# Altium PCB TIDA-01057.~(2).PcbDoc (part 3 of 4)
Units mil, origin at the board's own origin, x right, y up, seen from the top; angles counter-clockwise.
Board outline 4448 x 3930 mil, 4 copper layers (Layer 1 - Top Layer, Layer 2 - GND, Layer 3 - PWR, Layer 4 - Bottom Layer), stack 59.034 mil thick; 536 components, 284 nets, 1540 pads, 770 vias.

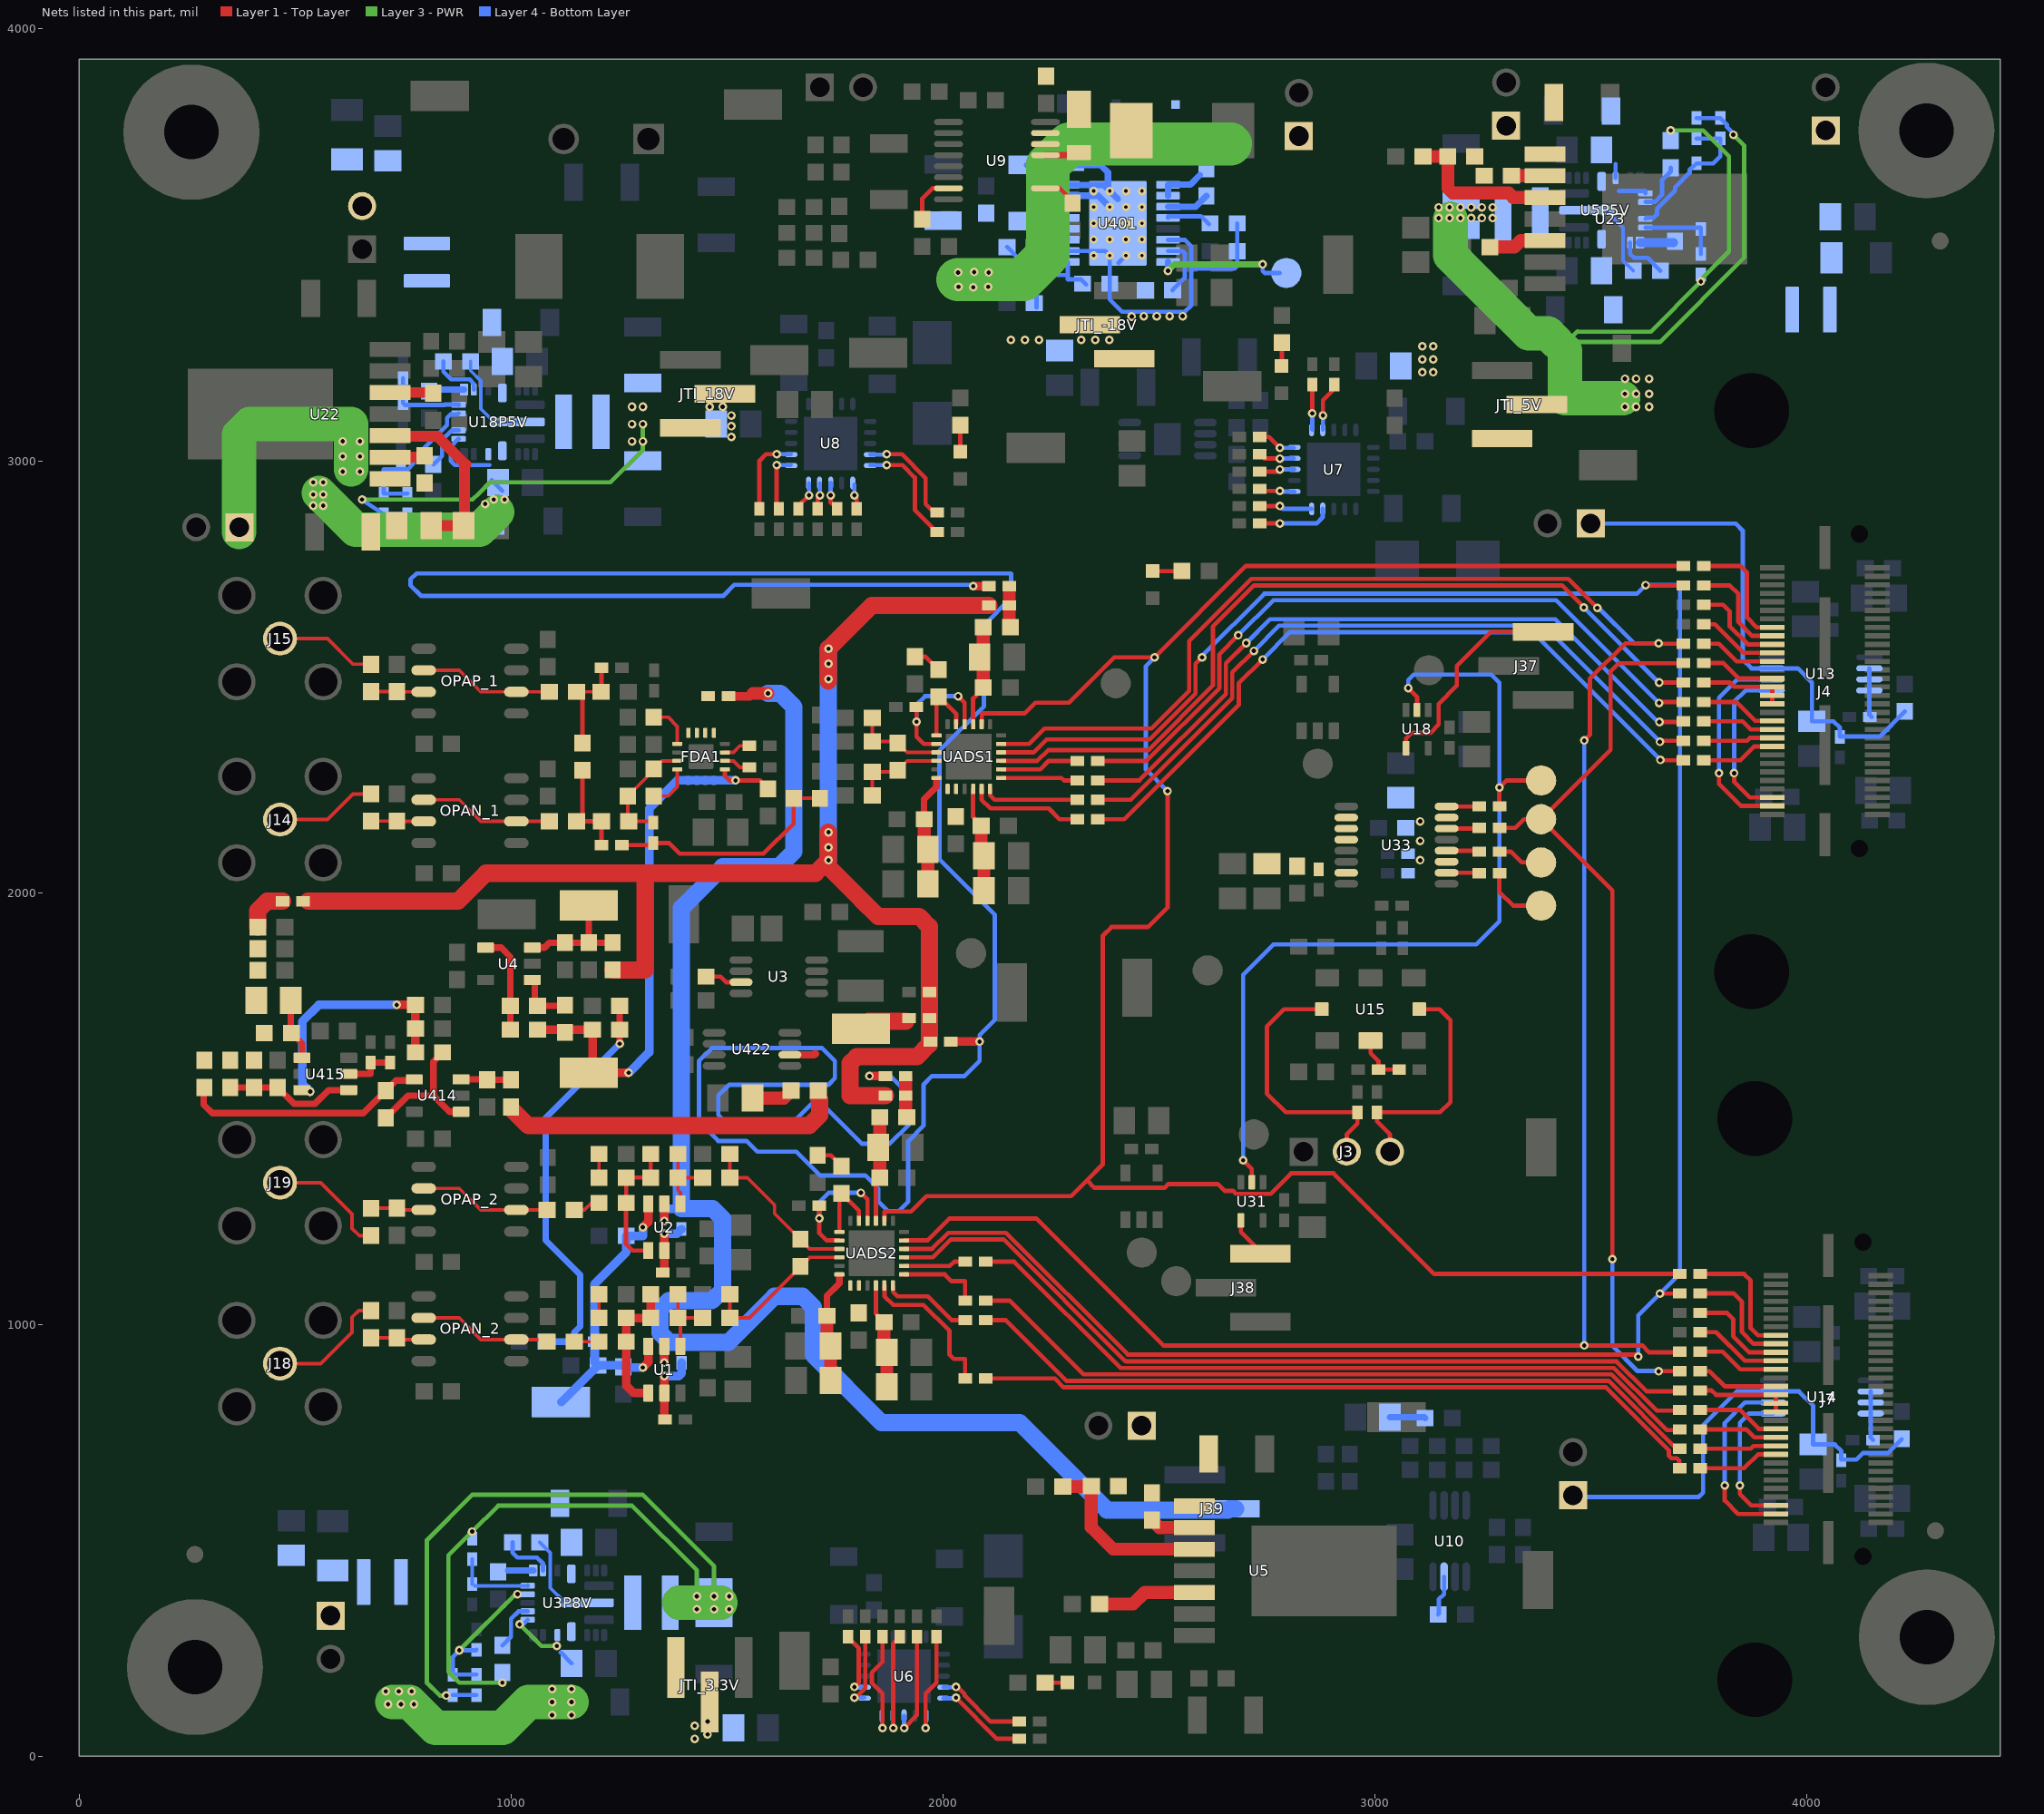
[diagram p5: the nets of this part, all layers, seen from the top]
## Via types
v1: diameter 20, hole 10, Layer 1 - Top Layer to Layer 4 - Bottom Layer, tented both sides, 382 vias
v2: diameter 20, hole 10, Layer 1 - Top Layer to Layer 4 - Bottom Layer, 258 vias
v3: diameter 20, hole 10, Layer 1 - Top Layer to Layer 4 - Bottom Layer, tented bottom, 57 vias
v4: diameter 19.68, hole 7.87, Layer 1 - Top Layer to Layer 4 - Bottom Layer, tented both sides, 48 vias
v5: diameter 20, hole 10, Layer 1 - Top Layer to Layer 4 - Bottom Layer, tented top, 19 vias
v6: diameter 19.68, hole 7.87, Layer 1 - Top Layer to Layer 4 - Bottom Layer, 6 vias

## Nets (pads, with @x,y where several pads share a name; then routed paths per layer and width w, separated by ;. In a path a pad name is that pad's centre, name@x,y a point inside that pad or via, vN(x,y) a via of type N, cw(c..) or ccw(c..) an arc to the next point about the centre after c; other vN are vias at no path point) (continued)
NetC87_2: C87.2 R100.2 RMFBP2.1 RMFBP.1 | length 557.4
  Layer 1 - Top Layer w8: C87.2@1654,2217.25 C87.2@1655,2218.25 R100.2@1715,2218.25
  Layer 1 - Top Layer w10: RMFBP.1@1256.62,2110 1324.62,2110 RMFBP2.1@1329,2114.38 1366.23,2114.38 1390.86,2089.75 1584.14,2089.75 1654,2159.6 C87.2@1654,2217.25
NetC88_2: C88.2 UADS1.13 UADS1.14
NetC89_1: C89.1 C315.1 R103.2 UADS1.10 | length 209.2
  Layer 1 - Top Layer w8: C89.1@1836.5,2224.75 R103.2@1836.5,2279.75 C315.1@1891.5,2279.75 ; C315.1@1895,2283.25 1916.65,2304.9 UADS1.10@1985.2,2304.9
NetC90_1: C90.1 C315.2 R104.2 UADS1.9 | length 209.2
  Layer 1 - Top Layer w8: C90.1@1836.5,2404.75 R104.2@1836.5,2349.75 C315.2@1891.5,2349.75 ; C315.2@1895,2346.24 1916.65,2324.59 UADS1.9@1985.2,2324.59
NetC91_2: C91.2 C287.1 L8.2 UADS1.12 | length 258.4
  Layer 1 - Top Layer w15: C91.2@1956.5,2169.75 1956.5,2216.24 1985.2,2244.94 UADS1.12@1985.2,2262.75
  Layer 1 - Top Layer w30: C91.2@1956.5,2169.75 1956.5,2108.25 C287.1@1965,2099.75 L8.2@1965,2019.75
NetC92_1: C92.1 C288.1 L9.2 UADS1.16 | length 245.6
  Layer 1 - Top Layer w10: UADS1.16@2069.84,2239.94 2069.84,2174.9 2088.5,2156.24 C92.1@2088.5,2154.75
  Layer 1 - Top Layer w30: C92.1@2088.5,2154.75 2088.5,2091.24 C288.1@2095,2084.75 L9.2@2095,2004.75
NetC93_1: C93.1 C289.1 R258.1 UADS1.3 | length 242
  Layer 1 - Top Layer w10: UADS1.3@2069.84,2389.55 2069.84,2449.59 2093.5,2473.25 C93.1@2093.5,2474.75
  Layer 1 - Top Layer w30: C93.1@2093.5,2474.75 2093.5,2536.24 C289.1@2085,2544.75 2093.5,2553.25 R258.1@2093.5,2614.75
NetC110_1: C110.1 R113.2 | length 55
  Layer 1 - Top Layer w8: C110.1@1203.5,1014.75 R113.2@1203.5,1069.75
NetC110_2: C110.2 C111.2 R114.1 RDP4.1 U1.4 | length 326.9
  Layer 1 - Top Layer w20: U1.4@1317.6,840.61 1284.13,840.61 1266.5,858.25 C110.2@1266.5,1014.75 C111.2@1323.5,1014.75 R114.1@1323.5,1069.75
NetC111_1: C111.1 R114.2 R115.1 U1.1 | length 180.3
  Layer 1 - Top Layer w8: R114.2@1386.5,1069.75 C111.1@1386.5,1014.75 ; U1.1@1392.4,948.88 1392.4,1008.84 C111.1@1386.5,1014.75 ; R115.1@1443.5,1014.75 C111.1@1386.5,1014.75
NetC113_1: C113.1 C114.2 R116.1 RDN4.1 U2.4 | length 324
  Layer 1 - Top Layer w10: U2.4@1317.6,1170.61 1281.06,1170.61 1266.18,1185.49 1266.18,1280.68 RDN4.1@1266.5,1281 C113.1@1266.5,1339.75 C114.2@1323.5,1339.75 R116.1@1323.5,1394.75
NetC113_2: C113.2 R112.2 | length 55
  Layer 1 - Top Layer w8: C113.2@1203.5,1339.75 R112.2@1203.5,1394.75
NetC114_1: C114.1 R116.2 R117.1 U2.1 | length 175.3
  Layer 1 - Top Layer w8: R116.2@1386.5,1394.75 C114.1@1386.5,1339.75 ; U2.1@1392.4,1278.88 1392.4,1304.75 1386.5,1310.65 C114.1@1386.5,1339.75 ; R117.1@1443.5,1339.75 C114.1@1386.5,1339.75
NetC117_1: C117.1 C335.2 R117.2 UADS2.9 | length 386.5
  Layer 1 - Top Layer w8: C117.1@1506.5,1394.75 R117.2@1506.5,1339.75 1547,1339.75 1610,1276.75 1610,1256.75 C335.2@1668.5,1198.24 ; C335.2@1670,1196.24 1691.65,1174.59 UADS2.9@1760.2,1174.59
NetC118_1: C118.1 C335.1 R115.2 UADS2.10 | length 364.4
  Layer 1 - Top Layer w8: C118.1@1506.5,1069.75 R115.2@1506.5,1014.75 1552,1014.75 C335.1@1668.5,1131.25 ; C335.1@1670,1133.25 1691.65,1154.9 UADS2.10@1760.2,1154.9
NetC119_1: C119.1 UADS2.13 UADS2.14
NetC120_2: C120.2 C306.1 L6.2 UADS2.12 | length 258.4
  Layer 1 - Top Layer w15: C120.2@1731.5,1019.75 1731.5,1066.24 1760.2,1094.94 UADS2.12@1760.2,1112.75
  Layer 1 - Top Layer w30: C120.2@1731.5,1019.75 1731.5,958.25 C306.1@1740,949.75 L6.2@1740,869.75
NetC121_1: C121.1 C307.1 L7.2 UADS2.16 | length 245.6
  Layer 1 - Top Layer w10: UADS2.16@1844.84,1089.94 1844.84,1024.9 1863.5,1006.24 C121.1@1863.5,1004.75
  Layer 1 - Top Layer w30: C121.1@1863.5,1004.75 1863.5,941.24 C307.1@1870,934.75 L7.2@1870,854.75
NetC122_1: C122.1 C308.1 R261.1 UADS2.3 | length 247.2
  Layer 1 - Top Layer w10: UADS2.3@1844.84,1239.55 C122.1@1844.84,1339.75
  Layer 1 - Top Layer w30: C122.1@1853.5,1339.75 1853.5,1401.24 1845,1409.75 1853.5,1418.25 R261.1@1853.5,1479.75
NetC316_1: C316.1 FDA1.4 | length 104.3
  Layer 1 - Top Layer w8: C316.1@1330,2223.25 1363.5,2223.25 1384.88,2244.63 FDA1.4@1384.88,2285.22
NetC316_2: C316.2 FDA1.3 R99.2 RDP2.1 RMFBP2.2 | length 267.6
  Layer 1 - Top Layer w8: RMFBP2.2@1329,2161.62 1325.62,2165 RDP2.1@1272.5,2165 1270,2167.5 R99.2@1270,2223.25 1330,2283.25 C316.2@1330,2286.24 1348.66,2304.9 FDA1.3@1384.88,2304.9
NetC317_1: C317.1 FDA1.1 | length 104.3
  Layer 1 - Top Layer w8: C317.1@1330,2406.24 1363.5,2406.24 1384.88,2384.86 FDA1.1@1384.88,2344.27
NetC319_1: C319.1 R215.1 U4.1 | length 129.5
  Layer 1 - Top Layer w15: U4.1@1049.13,1797.6 1055,1791.74 1055,1743.87 C319.1@1061.5,1737.38 1123.5,1737.38 R215.1@1125,1738.87
NetC319_2: C319.2 R216.1 U4.4 | length 235.2
  Layer 1 - Top Layer w15: U4.4@940.87,1872.41 977.28,1872.41 998.5,1851.19 C319.2@998.5,1737.38 R216.1@998.5,1682.38
NetC321_1: C321.1 R217.2 R218.1 TP28.1 U4.3 | length 276.7
  Layer 1 - Top Layer w15: U4.3@1049.13,1872.41 1077.4,1872.41 1088.87,1883.87 C321.1@1125,1883.87 R217.2@1180,1883.87 ; TP28.1@1180,1970 R217.2@1180,1883.87 ; R218.1@1235,1883.87 R217.2@1180,1883.87
NetC322_2: C322.2 R268.2 | length 67.4
  Layer 1 - Top Layer w10: R268.2@1935,2546.24 1960,2546.24 C322.2@1990,2516.24
NetC323_2: C323.2 R269.2 | length 65.4
  Layer 1 - Top Layer w10: R269.2@1710,1391.24 1740,1391.24 C323.2@1765,1366.24
NetC355_1: C355.1 C356.1 JSI_3.3V.1 L20.1
NetC357_1: C357.1 C358.1 C359.1 C360.1 L20.2 U3P8V.4 U3P8V.14 U3P8V.15 U3P8V.18 | length 619.3
  Layer 3 - PWR w10: v2(1020,305) 1070,255 v3(1106,255)
  Layer 3 - PWR w80: 725,125 760,125 765.29,125 825.29,65 980,65 1040,125 v2(1095,125) v2(1140,125)
  Layer 4 - Bottom Layer w10: v2@1029.61,306.77 U3P8V.18@1038.46,315.63 ; C360.1@1115,240 C360.1@1140,215
  other v2: 1095,95 715,120 745,120 775,120 740,150 1095,155
  other v3: 1140,95 710,150 770,150 1140,155
NetC361_1: C361.1 U3P8V.2 | length 120.7
  Layer 4 - Bottom Layer w10: C361.1@1003.5,495 1003.5,471.5 1015,460 1060,460 1073.9,446.1 U3P8V.2@1073.9,429.8
NetC361_2: C361.2 L21.1 U3P8V.9 | length 164.7
  Layer 4 - Bottom Layer w8: C361.2@1066.5,495 1090.63,470.87 1090.63,389.37 1108,372 1108.73,372 1114,366.73 1114,366 U3P8V.9@1125,355
NetC362_1: C362.1 RB3.1 U3P8V.22 | length 181.2
  Layer 4 - Bottom Layer w8: C362.1@910,398.62 RB3.1@910,456.38 ; C362.1@915.63,394.37 U3P8V.22@1038.46,394.37
  Layer 4 - Bottom Layer w10: U3P8V.22@1038.46,394.37 U3P8V.22@1038.46,395
NetC363_1: C363.1 R290.2 R291.2 U3P8V.21 | length 347
  Layer 1 - Top Layer w10: v2@1010,375 v2(1015,375)
  Layer 3 - PWR w10: v2(880,245) v2@1010,375
  Layer 4 - Bottom Layer w10: C363.1@920,188.62 R291.2@865,188.62 865,230 v2(880,245) 918.62,245 R290.2@920,246.38
NetC363_2: C363.2 C364.1 C366.1 JTI_3.3V.1 L21.2 R291.1 RB3.2 RES3V.1 | length 2534.4
  Layer 3 - PWR w10: v3(850,140) 835,140 805,170 805,500 910,605 1305,605 1470,440 v2(1470,370) ; v3(980,170) 880,170 855,195 855,465 v3(910,520) 970,580 1280,580 1430,430 v2(1430,370)
  Layer 3 - PWR w80: 1389.96,355 1485,355
  Layer 4 - Bottom Layer w10: R291.1@865,141.38 C363.2@920,141.38
  other v2: 1430,340 1470,340 1505,340 1505,370
NetC367_1: C367.1 C368.1 JSI_5V.1 L22.1
NetC369_1: C369.1 C370.1 C371.1 C372.1 L22.2 U5P5V.4 U5P5V.14 U5P5V.15 U5P5V.18 | length 100
  Layer 4 - Bottom Layer w10: U5P5V.15@3557.64,3654.8 3557.64,3687.64 ; 3565,3625 3626.54,3625 U5P5V.18@3626.54,3619.37
NetC373_1: C373.1 U5P5V.2 | length 114.7
  Layer 4 - Bottom Layer w10: U5P5V.2@3589.75,3503.85 U5P5V.2@3591.1,3505.2 3591.1,3478.9 3600,3470 3631.5,3470 C373.1@3661.5,3440
NetC373_2: C373.2 L23.1 U5P5V.9 | length 166.3
  Layer 4 - Bottom Layer w8: U5P5V.9@3535,3580 3575,3540 3575,3463.5 C373.2@3598.5,3440
NetC374_1: C374.1 R294.2 R295.2 U5P5V.21 | length 345.6
  Layer 4 - Bottom Layer w10: U5P5V.21@3626.54,3560.31 3629.33,3563.11 3645.8,3563.11 3653.27,3570.58 3653.27,3583.27 3695.13,3625.13 3695.13,3633.21 3729.05,3667.13 3729.05,3674.05 3730,3675 R294.2@3745,3688.62 3783.62,3688.62 3800,3705 R295.2@3800,3746.38 C374.1@3745,3746.38
NetC374_2: C374.2 C376.1 C378.1 JTI_5V.1 L23.2 R295.1 RB5.2 RES5V.1 | length 2441.5
  Layer 3 - PWR w10: 3420,3275 3445.2,3275 ; 3440,3255 3440,3269.8 3445.2,3275 ; v3(3685,3765) 3760,3765 3820,3705 3820,3485 3755,3420 v3(3755,3415) 3639,3299 3469.94,3299 3469.57,3299.37 3445.2,3275 ; v3(3830,3755) 3855,3730 3855,3470 3660,3275 3445.2,3275
  Layer 3 - PWR w80: v2@3175,3560 3175,3476 3356,3295 3400,3295 3420,3275 ; 3440,3255 3440,3145 3575,3145
  Layer 4 - Bottom Layer w10: C374.2@3745,3793.62 R295.1@3800,3793.62 3815,3778.62 3815,3773.08 3830,3758.08 v3(3830,3755)
  other v2: 3579,3125 3605,3125 3635,3125 3579,3155 3605,3155 3635,3155 3579,3190 3605,3190 3635,3190 3148,3562 3173,3562 3198,3562 3223,3562 3248,3562 3273,3562 3148,3587 3173,3587 3198,3587 3223,3587 3248,3587 3273,3587
NetC375_1: C375.1 RB5.1 U5P5V.22 | length 187.7
  Layer 4 - Bottom Layer w10: RB5.1@3755,3478.62 C375.1@3755,3536.38 ; C375.1@3755,3540 U5P5V.22@3627.17,3540 ; U5P5V.22@3627.17,3540 3626.54,3540 U5P5V.22@3626.54,3540.63 U5P5V.22@3627.17,3540
NetC379_1: C379.1 C380.1 JSI_18V.2 L24.1
NetC381_1: C381.1 C382.1 C383.1 C384.1 L24.2 U18P5V.4 U18P5V.14 U18P5V.15 U18P5V.18 | length 653
  Layer 3 - PWR w80: 555,2925 640,2840 927,2840 968,2881
  Layer 4 - Bottom Layer w10: U18P5V.18@878.46,3050.63 860,3032.17 860,3000 870,2990 950,2990 ; C384.1@955,2955 C384.1@980,2930
  other v2: 542,2896 565,2896 940,2900 985,2910 542,2922 565,2922 542,2950 565,2950
  other v3: 960,2910
NetC385_1: C385.1 U18P5V.2 | length 120.7
  Layer 4 - Bottom Layer w10: C385.1@843.5,3230 843.5,3206.5 861.42,3188.58 903.8,3188.58 913.9,3178.49 U18P5V.2@913.9,3164.8 U18P5V.2@915,3165.91
NetC385_2: C385.2 L25.1 U18P5V.9 | length 216.5
  Layer 4 - Bottom Layer w8: C385.2@906.5,3230 906.5,3208.5 929.79,3185.21 929.79,3120.15 959.94,3090 U18P5V.9@1014.29,3090
NetC387_1: C387.1 R297.2 R298.2 U18P5V.21 | length 354.8
  Layer 4 - Bottom Layer w10: C387.1@760,2923.62 R298.2@705,2923.62 705,2980 760,2980 775,2995 775,3006.22 851.73,3082.95 851.73,3099.42 859.2,3106.89 875.67,3106.89 U18P5V.21@878.46,3109.69
NetC387_2: C387.2 C389.1 C391.1 JTI_18V.1 L25.2 R298.1 | length 862.9
  Layer 3 - PWR w10: v2(655,2910) 911,2910 926,2925 951,2950 1230,2950 1305,3025 1305,3075
  Layer 4 - Bottom Layer w10: v2(655,2910) R298.1@705,2876.38 C387.2@760,2876.38
  other v2: 1280,3045 1305,3045 1280,3125 1305,3125
  other v3: 1280,3085 1305,3085
NetC388_1: C388.1 RB18.1 U18P5V.22 | length 188.9
  Layer 4 - Bottom Layer w10: RB18.1@750,3191.38 C388.1@750,3133.62 754.25,3129.37 846.09,3129.37 846.72,3130 878.46,3130 U18P5V.22@878.46,3129.37
NetC401_1: C401.1 C402.1 C408.1 JPRI_-18V.1 U401.12 U401.13 U401.14 | length 882.9
  Layer 3 - PWR w100: 2035,3420 2186,3420 2243,3477 2243,3685 2292,3734 2666,3734
  other v2: 2070,3402 2036,3403 2105,3403 2035,3436 2106,3436 2072,3437
NetC403_1: C403.1 U401.4 | length 106
  Layer 4 - Bottom Layer w10: U401.4@2521.14,3562.8 2521.14,3566.18 2597.32,3566.18 C403.1@2616,3547.5
NetC403_2: C403.2 C405.2 C406.2 C407.2 C408.2 JTI_-18V.3 R401.1 R404.1 U401.6 U401.10 U401.15 U401.16 U401.17@2405,3550 | length 1487.3
  Layer 4 - Bottom Layer w10: C407.2@2148.5,3495 2173.5,3470 2183.97,3470 2187.67,3466.3 2235.32,3466.3 2255.05,3486.02 U401.10@2288.86,3486.02 2338.07,3486.02 ; U401.16@2288.86,3639.57 U401.16@2289.61,3638.82 ; v4(2348.9,3475.2) 2338.07,3486.02 ; U401.17@2406.5,3457.99 v4(2423.7,3475.2) ; v4(2461.1,3512.6) U401.17@2462.09,3511.61 ; U401.6@2521.14,3511.61 2560,3511.61 2575,3496.61 2575,3445 ; C403.2@2681.5,3550 C405.2@2681.5,3485 2681.5,3451.5 2675,3445 2575,3445 ; 2338.07,3486.02 2375.47,3486.02 v4(2386.3,3475.2) 2386.3,3373.7 2415,3345 2560,3345 2575,3360 2575,3445
  Layer 4 - Bottom Layer w15: C408.2@2195,3684.96 2365,3685 2381.93,3668.07 U401.17@2381.93,3629.17 ; U401.15@2288.86,3613.98 2359.72,3613.98 v6(2386.3,3587.4) ; U401.16@2289.61,3638.82 2372.29,3638.82 U401.17@2381.93,3629.17 ; U401.17@2405,3606.1 v4(2386.3,3624.8) U401.17@2381.93,3629.17
  other v2: 2437,3334 2465,3335 2495,3335 2525,3335 2555,3335
  other v4: 2461.1,3475.2 2348.9,3512.6 2348.9,3550 2461.1,3550 2348.9,3587.4 2461.1,3587.4 2348.9,3624.8 2423.7,3624.8 2461.1,3624.8
  other v6: 2386.3,3512.6 2423.7,3512.6 2386.3,3550 2423.7,3550 2423.7,3587.4
NetC404_1: C404.1 U401.3 | length 99.3
  Layer 4 - Bottom Layer w15: U401.3@2521.14,3588.39 2584.88,3588.39 C404.1@2610,3613.5
NetC404_2: C404.2 L401.1 U401.1 U401.2 | length 108.5
  Layer 4 - Bottom Layer w15: U401.2@2521.14,3613.98 U401.1@2521.14,3639.57 2573.07,3639.57 C404.2@2595,3661.5
NetC407_1: C407.1 U401.11 | length 87.9
  Layer 4 - Bottom Layer w11: C407.1@2211.5,3495 2230.7,3514.2 2288.86,3514.2 U401.11@2288.86,3511.61
NetC409_2: C409.2 R401.2 R402.1 U401.9 | length 230.6
  Layer 4 - Bottom Layer w10: R402.1@2211.5,3430 2288.86,3430 ; C409.2@2216.5,3355 R402.1@2216.5,3420 ; U401.9@2288.86,3460.43 2288.86,3430 ; R401.2@2331.69,3408.05 2319.75,3420 2288.86,3420 2288.86,3430
NetC452_1: C452.1 C457.1 C458.1 C459.1 C461.1 R457.1 R489.2 R492.2 R494.2 | length 105.3
  Layer 1 - Top Layer w40: C457.1@413.5,1919.75 413.5,1958.25 435,1979.75 R457.1@471.38,1979.75
NetC452_2: C452.2 R489.1 U415.1 | length 143.7
  Layer 1 - Top Layer w15: C452.2@489.55,1763.74 C452.2@489.83,1764.02 ; C452.2@490,1749.75 490,1676.24 R489.1@491.5,1674.75 515.87,1650.38 U415.1@515.87,1617.15
NetC453_1: C453.1 R485.2 U414.3 | length 115
  Layer 1 - Top Layer w15: U414.3@884.13,1567.15 C453.1@944.09,1567.15 ; C453.1@945,1566.24 R485.2@1000,1566.24
NetC454_1: C454.1 R486.2 R488.2 U415.3 | length 557.5
  Layer 1 - Top Layer w20: v5(735,1739.75) C454.1@778.5,1739.75 R488.2@778.5,1684.75 R486.2@778.5,1629.75
  Layer 4 - Bottom Layer w20: v2(534.83,1539.02) 516.8,1557.04 516.8,1701.55 555,1739.75 v5(735,1739.75)
NetC460_1: C460.1 R486.1 U414.1 | length 319.8
  Layer 1 - Top Layer w15: C460.1@710,1478.25 761.5,1529.75 820.2,1529.75 ; R486.1@841.5,1629.75 820.2,1608.45 820.2,1529.75 ; U414.1@884.13,1492.34 857.6,1492.34 820.2,1529.75
NetC460_2: C460.2 R494.1 U414.4 | length 571.6
  Layer 1 - Top Layer w15: R494.1@289.7,1548.5 288.2,1550 288.2,1508.8 308,1489 657.76,1489 C460.2@710,1541.24 733.5,1564.75 773.46,1564.75 U414.4@775.87,1567.15
NetC461_2: C461.2 R491.2 R492.1 U415.4 | length 310.8
  Layer 1 - Top Layer w15: R492.1@344.7,1542.95 R492.1@350.26,1548.5 ; R492.1@349.7,1548.5 R492.1@350.26,1548.5 ; U415.4@624.13,1542.34 577.6,1542.34 546.25,1511 496.95,1511 R491.2@459.7,1548.25 404.95,1548.25 C461.2@404.7,1548.5 R492.1@350.26,1548.5
NetCin1_1: Cin1.1 JZI_18V.1 Rent.2 Ron.2 U22.1 | length 600.4
  Layer 3 - PWR w80: JZI_18V.1@370,2835 370,3060 395,3085 630,3085 630,2980
  other v2: 610,2975 650,2975 610,3010 650,3010 610,3045 650,3045
NetCin2_1: Cin2.1 JZI_5V.1 Rent2.2 Ron2.2 U23.1
NetCin3_1: Cin3.1 JZI_3.3V.1 Rent3.2 Ron3.2 U5.1
NetCMFB_1: CMFB.1 RDP1.2 RDP2.2 RMFBP.2 | length 237.3
  Layer 1 - Top Layer w10: CMFB.1@1165,2283.25 1165,2178.25 RDP1.2@1151.5,2164.75 1209.25,2164.75 RDP2.2@1209.5,2165 1209.5,2110.13 RMFBP.2@1209.38,2110
NetCMFB_2: CMFB.2 RDN1.2 RDN2.2 RMFBN.1 | length 237.3
  Layer 1 - Top Layer w8: RDN1.2@1151.5,2464.75 RDN2.2@1208.5,2464.75 RDN2.2@1209.38,2465.62
  Layer 1 - Top Layer w10: RDN1.2@1151.5,2464.75 1165,2451.24 CMFB.2@1165,2346.24 ; RDN2.2@1209.38,2465.62 RMFBN.1@1209.38,2520.55
NetCR481_1: CR481.1 RR413.1 | length 96.5
  Layer 1 - Top Layer w30: CR481.1@1559,1524 1631.5,1524 RR413.1@1648.5,1541
NetCss2_1: Css2.1 U23.5 | length 134.1
  Layer 1 - Top Layer w30: Css2.1@3266.5,3495 3323,3495 3338,3510 U23.5@3394.37,3510
NetCss3_1: Css3.1 U5.5 | length 231.1
  Layer 1 - Top Layer w30: Css3.1@2362.5,352 2440,352 2467,379 U5.5@2582.37,379
NetCss_2: Css.2 U22.5 | length 98.9
  Layer 1 - Top Layer w25: U22.5@719.63,3158 Css.2@818.5,3158
NetCVCC3V_1: CVCC3V.1 U3P8V.1 | length 57.6
  Layer 4 - Bottom Layer w15: 993.62,429.8 U3P8V.1@1051.26,429.8
NetCVCC5V_1: CVCC5V.1 U5P5V.1 | length 82.6
  Layer 4 - Bottom Layer w10: CVCC5V.1@3691.69,3505.2 CVCC5V.1@3695,3508.5
  Layer 4 - Bottom Layer w20: U5P5V.1@3613.74,3505.2 CVCC5V.1@3691.69,3505.2
NetCVCC18V_1: CVCC18V.1 U18P5V.1 | length 82.6
  Layer 4 - Bottom Layer w15: CVCC18V.1@810,3161.5 813.31,3164.8 U18P5V.1@891.26,3164.8
NetD2_2: D2.2 U9.13 | length 80.3
  Layer 1 - Top Layer w10: D2.2@2308.99,3707.8 D2.2@2315,3713.8
  Layer 1 - Top Layer w14: U9.13@2237.2,3707.8 D2.2@2308.99,3707.8
NetD14_2: D14.2 R46.1 | length 52
  Layer 1 - Top Layer w10: R46.1@2236.5,170 D14.2@2288.5,170
NetD18_2: D18.2 R47.1 | length 67.7
  Layer 1 - Top Layer w10: D18.2@2486,2744.5 2553,2744.5 R47.1@2553.5,2745
NetD21_2: D21.2 R246.1 | length 54.5
  Layer 1 - Top Layer w10: D21.2@2783.32,3219.73 2785,3221.42 R246.1@2785,3273.5
NetD22_2: D22.2 R247.1 | length 61
  Layer 1 - Top Layer w10: D22.2@2040,3021.5 R247.1@2040,3082.52
NetFDA1_10: FDA1.10 R211.1 | length 62.5
  Layer 1 - Top Layer w8: FDA1.10@1495.12,2304.9 1514.84,2304.9 1530,2289.75 R211.1@1551.38,2289.75
NetFDA1_11: FDA1.11 R212.1 | length 62.5
  Layer 1 - Top Layer w8: FDA1.11@1495.12,2324.59 1514.84,2324.59 1530,2339.75 R212.1@1551.38,2339.75
NetFDA1_13: FDA1.13 FDA1.14 FDA1.15 FDA1.16 R248.1
NetJ4_16: J4.16 R65.2 | length 278.6
  Layer 1 - Top Layer w10: R65.2@3762.01,2756.39 3846.52,2756.39 3861.52,2741.39 3861.52,2636.88 3884.21,2614.19 J4.16@3920.51,2614.19
NetJ4_18: J4.18 R66.2 | length 245.4
  Layer 1 - Top Layer w10: R66.2@3761.36,2711.39 3821.52,2711.39 3841.52,2691.39 3841.52,2626.88 3873.91,2594.49 J4.18@3920.51,2594.49
NetJ4_20: J4.20 R67.2 | length 217.3
  Layer 1 - Top Layer w10: R67.2@3761.36,2666.39 3806.52,2666.39 3821.52,2651.39 3821.52,2616.88 3863.61,2574.79 J4.20@3920.51,2574.79
NetJ4_22: J4.22 R68.2 | length 186.6
  Layer 1 - Top Layer w10: R68.2@3761.36,2621.39 3787.01,2621.39 3853.31,2555.09 J4.22@3920.51,2555.09
NetJ4_24: J4.24 R69.2 | length 176.1
  Layer 1 - Top Layer w10: R69.2@3761.36,2576.39 3796.52,2576.39 3837.52,2535.39 J4.24@3920.51,2535.39
NetJ4_28: J4.28 R70.2 | length 173.8
  Layer 1 - Top Layer w10: R70.2@3761.36,2531.39 3807.01,2531.39 3842.41,2495.99 J4.28@3920.51,2495.99
NetJ4_30: J4.30 J4.32 J4.34 R71.2 | length 202.2
  Layer 1 - Top Layer w10: R71.2@3761.36,2486.39 3822.01,2486.39 3832.11,2476.29 J4.30@3920.02,2476.29 ; J4.34@3920.51,2436.89 J4.32@3920.51,2456.59 J4.30@3920.51,2476.29
NetJ4_38: J4.38 R72.2 | length 177.3
  Layer 1 - Top Layer w10: R72.2@3761.36,2441.39 3836.52,2441.39 3880.42,2397.49 J4.38@3920.51,2397.49
NetJ4_40: J4.40 R73.2 | length 166.8
  Layer 1 - Top Layer w10: R73.2@3761.36,2396.39 3851.52,2396.39 3870.12,2377.79 J4.40@3920.51,2377.79
NetJ4_42: J4.42 R74.2 | length 161.9
  Layer 1 - Top Layer w10: R74.2@3761.36,2351.39 3861.52,2351.39 3868.22,2358.09 J4.42@3920.51,2358.09
NetJ4_44: J4.44 R75.2 | length 172.4
  Layer 1 - Top Layer w10: R75.2@3761.36,2306.39 3846.52,2306.39 3878.52,2338.39 J4.44@3920.51,2338.39
NetJ7_16: J7.16 R76.2 | length 303.2
  Layer 1 - Top Layer w10: R76.2@3748.65,1116.69 3855.03,1116.69 3870.03,1101.69 3870.03,991.69 3887.23,974.49 J7.16@3928.52,974.49
NetJ7_18: J7.18 R77.2 | length 269.3
  Layer 1 - Top Layer w10: R77.2@3748.65,1071.69 3830.03,1071.69 3850.03,1051.69 3850.03,981.69 3876.93,954.79 J7.18@3928.52,954.79
NetJ7_20: J7.20 R78.2 | length 241.2
  Layer 1 - Top Layer w10: R78.2@3748.65,1026.69 3815.03,1026.69 3830.03,1011.69 3830.03,971.69 3866.63,935.09 J7.20@3928.52,935.09
NetJ7_22: J7.22 R79.2 | length 207.3
  Layer 1 - Top Layer w10: R79.2@3748.65,981.69 3790.03,981.69 3856.33,915.39 J7.22@3928.52,915.39
NetJ7_24: J7.24 R80.2 | length 196.9
  Layer 1 - Top Layer w10: R80.2@3748.65,936.69 3805.03,936.69 3846.03,895.69 J7.24@3928.52,895.69
NetJ7_28: J7.28 R81.2 | length 194.5
  Layer 1 - Top Layer w10: R81.2@3748.65,891.69 3775.03,891.69 3810.43,856.29 J7.28@3928.52,856.29
NetJ7_30: J7.30 J7.32 J7.34 R82.2 | length 223.5
  Layer 1 - Top Layer w10: R82.2@3748.65,846.69 3780.03,846.69 3790.13,836.59 J7.30@3928.52,836.59 J7.32@3928.52,816.89 J7.34@3928.52,797.19
NetJ7_38: J7.38 R83.2 | length 198.1
  Layer 1 - Top Layer w10: R83.2@3748.65,801.69 3845.03,801.69 3888.93,757.79 J7.38@3928.52,757.79
NetJ7_40: J7.40 R84.2 | length 187.6
  Layer 1 - Top Layer w10: R84.2@3748.65,756.69 3860.03,756.69 3878.63,738.09 J7.40@3928.52,738.09
NetJ7_42: J7.42 R85.2 | length 182.6
  Layer 1 - Top Layer w10: R85.2@3748.65,711.69 3870.03,711.69 3876.73,718.39 J7.42@3928.52,718.39
NetJ7_44: J7.44 R86.2 | length 193.1
  Layer 1 - Top Layer w10: R86.2@3748.65,666.69 3855.03,666.69 3887.03,698.69 J7.44@3928.52,698.69
NetJ37_1: J37.1 U18.4 | length 500.2
  Layer 1 - Top Layer w10: U18.4@3070.13,2332.17 U18.4@3072.22,2334.25 3072.22,2356.96 3085,2369.75 3128.38,2369.75 3147.81,2389.17 3147.81,2436.99 3190,2479.18 3190,2524.75 3268.74,2603.49 J37.1@3389.96,2603.49
NetJ38_1: J38.1 U31.4 | length 120.5
  Layer 1 - Top Layer w10: U31.4@2689.62,1240.45 2689.62,1214.26 2735.39,1168.49 J38.1@2764.96,1168.49
NetJTI_3.3V_2: JTI_3.3V.2 L19.1
  other v2: 1425,40 1455,50 1425,70 1455,80
NetJTI_5V_2: JTI_5V.2 L18.1
  other v2: 3110,3205 3135,3205 3110,3235 3135,3235 3110,3265 3135,3265
NetJTI_18V_2: JTI_18V.2 L16.2
  other v2: 1510,3055 1510,3080 1510,3105 1460,3125 1490,3125
NetJTI_-18V_2: JTI_-18V.2 L17.2
  other v2: 2157.5,3280 2190,3280 2222.5,3280 2320,3280 2352.5,3280 2385,3280
NetL5_2: L5.2 R22.2 | length 82.4
  Layer 4 - Bottom Layer w15: L5.2@3035,785 3114.52,785 R22.2@3116.52,783
NetOPAN_1_2: OPAN_1.2 OPAN_1.6 RDP1.1 | length 311.5
  Layer 1 - Top Layer w8: OPAN_1.2@797.71,2214.74 879.99,2214.74 929.99,2164.74 OPAN_1.6@1012.28,2164.74 RDP1.1@1088.5,2164.75
NetOPAN_2_2: OPAN_2.2 OPAN_2.6 RDP3.1 | length 301.5
  Layer 1 - Top Layer w8: OPAN_2.2@797.72,1014.75 880,1014.75 930,964.75 OPAN_2.6@1012.28,964.75 RDP3.1@1078.5,964.75
NetOPAP_1_2: OPAP_1.2 OPAP_1.6 RDN1.1 | length 311.5
  Layer 1 - Top Layer w8: OPAP_1.2@797.72,2514.75 880,2514.75 930,2464.75 OPAP_1.6@1012.28,2464.75 RDN1.1@1088.5,2464.75
NetOPAP_2_2: OPAP_2.2 OPAP_2.6 RDN3.1 | length 306.2
  Layer 1 - Top Layer w8: OPAP_2.2@797.72,1314.75 880,1314.75 930,1264.75 OPAP_2.6@1012.28,1264.75 RDN3.1@1083.19,1264.75
NetR3_2: R3.2 U3.3 | length 86.2
  Layer 1 - Top Layer w10: R3.2@1451.5,1805.16 1484.79,1805.16 1497.58,1792.36 U3.3@1532.4,1792.36
NetR8_2: R8.2 U8.4 | length 251.2
  Layer 1 - Top Layer w10: v1(1870,3015) 1905,3015 1960,2960 1960,2900 1980,2880 R8.2@1991.38,2880
  Layer 4 - Bottom Layer w10: U8.4@1831.54,3014.41 1869.41,3014.41 v1(1870,3015)
NetR9_2: R9.2 U8.5 | length 275.9
  Layer 1 - Top Layer w10: v1(1870,2990) 1906.1,2990 1935,2961.1 1935,2886.38 ; 1935,2893.05 1935,2886.38 ; R9.2@1985,2835 R9.2@1986.38,2835 ; R9.2@1991.38,2835 R9.2@1986.38,2835 ; 1935,2886.38 R9.2@1986.38,2835
  Layer 4 - Bottom Layer w10: U8.5@1831.54,2990 v1(1870,2990)
NetR10_2: R10.2 U8.6 | length 58.1
  Layer 1 - Top Layer w10: v1(1795,2920) 1800,2915 R10.2@1800,2888.62
  Layer 4 - Bottom Layer w10: v1(1795,2920) U8.6@1795,2944.65
NetR11_2: R11.2 U8.8 | length 66.1
  Layer 1 - Top Layer w10: v1(1740,2920) 1740,2903.62 R11.2@1755,2888.62
  Layer 4 - Bottom Layer w10: v1(1740,2920) U8.8@1740,2948.46
NetR12_2: R12.2 U8.9 | length 61.3
  Layer 1 - Top Layer w10: R12.2@1710,2888.62 1710,2915 v1(1715,2920)
  Layer 4 - Bottom Layer w10: v1(1715,2920) U8.9@1715,2947.87
NetR13_2: R13.2 U8.10 | length 69
  Layer 1 - Top Layer w10: R13.2@1665,2888.62 1665,2895 v1(1690,2920)
  Layer 4 - Bottom Layer w10: v1(1690,2920) U8.10@1690,2947.28
NetR14_2: R14.2 U8.11 | length 135.7
  Layer 1 - Top Layer w10: v1(1615,2990) 1615,2893.62 R14.2@1620,2888.62
  Layer 4 - Bottom Layer w10: v1(1615,2990) U8.11@1647.28,2990
NetR15_2: R15.2 U8.12 | length 190.5
  Layer 1 - Top Layer w10: R15.2@1575,2888.62 1575,3000 1590,3015 v1(1615,3015)
  Layer 4 - Bottom Layer w10: v1(1615,3015) U8.12@1647.87,3015
NetR17_2: R17.2 U7.4 | length 170.8
  Layer 1 - Top Layer w10: R17.2@2733.62,2855 v2(2780,2855)
  Layer 4 - Bottom Layer w10: v2(2780,2855) 2865,2855 2879.41,2869.41 U7.4@2879.41,2888.46
NetR18_2: R18.2 U7.5 | length 117.9
  Layer 1 - Top Layer w10: R18.2@2733.62,2895 v2@2775,2895
  Layer 4 - Bottom Layer w10: v2(2780,2895) 2786.54,2888.46 U7.5@2853.82,2888.46
NetR19_2: R19.2 U7.6 | length 75.3
  Layer 1 - Top Layer w10: R19.2@2738.62,2930 v1(2780,2930)
  Layer 4 - Bottom Layer w10: v1(2780,2930) 2781.18,2928.82 U7.6@2813.46,2928.82
NetR20_2: R20.2 U7.8 | length 81.9
  Layer 1 - Top Layer w10: R20.2@2733.62,2975 2775,2975 v1(2780,2980)
  Layer 4 - Bottom Layer w10: v1(2780,2980) U7.8@2813.46,2980
NetR21_2: R21.2 U10.3 | length 93
  Layer 4 - Bottom Layer w10: R21.2@3146.52,328 3148.02,329.5 3148.02,363 3160.22,375.2 U10.3@3160.22,415.32
NetR24_2: R24.2 U7.9 | length 69.3
  Layer 1 - Top Layer w10: R24.2@2743.62,3005 v1(2780,3005)
  Layer 4 - Bottom Layer w10: v1(2780,3005) U7.9@2812.87,3005
NetR25_2: R25.2 U7.10 | length 89
  Layer 1 - Top Layer w10: R25.2@2733.62,3055 2755,3055 v1(2780,3030)
  Layer 4 - Bottom Layer w10: v1(2780,3030) U7.10@2812.28,3030
NetR26_2: R26.2 U7.11 | length 103.7
  Layer 1 - Top Layer w10: v1(2855,3110) R26.2@2855,3176.38
  Layer 4 - Bottom Layer w10: U7.11@2855,3072.72 v1(2855,3110)
NetR27_2: R27.2 U7.12 | length 122.1
  Layer 1 - Top Layer w10: v1@2875,3110 v1(2880,3105) 2880,3140 2906,3166 R27.2@2906,3176.38
  Layer 4 - Bottom Layer w10: U7.12@2880,3072.13 v1(2880,3105)
NetR29_2: R29.2 U6.4 | length 209.3
  Layer 1 - Top Layer w10: v1(2030,160) 2035,155 2038.28,155 2050,143.28 2050,140 2110,80 R29.2@2176.38,80
  Layer 4 - Bottom Layer w10: U6.4@2001.54,159.41 v1@2029.41,159.41
NetR30_2: R30.2 U6.5 | length 214.7
  Layer 1 - Top Layer w10: v1(2030,135) 2125,40 R30.2@2176.38,40
  Layer 4 - Bottom Layer w10: U6.5@2001.54,133.82 2028.82,133.82 v1(2030,135)
NetR31_2: R31.2 U6.6 | length 249
  Layer 1 - Top Layer w10: v1(1960,65) 1960,145 1985,170 R31.2@1985,276.38
  Layer 4 - Bottom Layer w10: v1(1960,65) U6.6@1960,92.28
NetR32_2: R32.2 U6.8 | length 252.3
  Layer 1 - Top Layer w10: v1(1910,65) 1940,95 R32.2@1940,276.38
  Layer 4 - Bottom Layer w10: v1(1910,65) U6.8@1910,93.46
NetR33_2: R33.2 U6.9 | length 245.5
  Layer 1 - Top Layer w10: v1(1885,65) 1885,261.38 R33.2@1900,276.38
  Layer 4 - Bottom Layer w10: v1(1885,65) U6.9@1885,92.87
NetR34_2: R34.2 U6.10 | length 259.2
  Layer 1 - Top Layer w10: v1(1860,65) 1860,144.91 1835.16,169.75 1835.16,193.22 1860,218.06 R34.2@1860,276.38
  Layer 4 - Bottom Layer w10: v1(1860,65) U6.10@1860,92.28
NetR35_2: R35.2 U6.11 | length 176.1
  Layer 1 - Top Layer w10: v1(1795,135) 1798.28,135 1820.16,156.87 1820.16,276.22 R35.2@1820,276.38
  Layer 4 - Bottom Layer w10: v1(1795,135) U6.11@1817.28,135
NetR36_2: R36.2 U6.12 | length 153.7
  Layer 1 - Top Layer w10: R36.2@1780,276.38 1780,274.68 1805,249.68 1805,170 v1(1795,160)
  Layer 4 - Bottom Layer w10: v1(1795,160) U6.12@1817.87,160
NetR50_2: R50.2 U9.7 | length 118.6
  Layer 1 - Top Layer w10: R50.2@1952.22,3559.06 1952.22,3607.22 1976.02,3631.02 U9.7@2012.8,3631.02
NetR90_2: R90.2 R91.2 U15.2@2990,1656.91 | length 122.6
  Layer 1 - Top Layer w10: U15.2@2990,1656.91 2990,1627.75 3008.62,1609.12 R91.2@3008.62,1589.75 R90.2@3056.38,1589.75
NetR95_1: R95.1 U33.16 | length 75.4
  Layer 1 - Top Layer w10: U33.16@3166.14,2199.31 3240.95,2199.31 R95.1@3241.38,2199.75
NetR223_1: R223.1 UADS2.17 | length 349
  Layer 1 - Top Layer w10: UADS2.17@1864.53,1089.94 1864.53,1065.22 1885,1044.75 1955,1044.75 2015,984.75 2015,929.75 2025,919.75 2051.38,919.75 R223.1@2051.38,874.75
NetR225_1: R225.1 UADS2.19 | length 193.1
  Layer 1 - Top Layer w10: UADS2.19@1909.8,1115.53 2004.21,1115.53 2020,1099.75 2051.38,1099.75 R225.1@2051.38,1054.75
NetR226_1: R226.1 UADS2.20 | length 145.6
  Layer 1 - Top Layer w10: UADS2.20@1909.8,1135.22 2016.01,1135.22 2025.79,1145 R226.1@2051.38,1145
NetR232_1: R232.1 UADS1.17 | length 265.4
  Layer 1 - Top Layer w10: UADS1.17@2089.53,2239.94 2089.53,2215.22 2110,2194.75 2245,2194.75 2270,2169.75 R232.1@2311.38,2169.75
NetR233_1: R233.1 UADS1.18 | length 221
  Layer 1 - Top Layer w10: UADS1.18@2109.21,2239.94 2109.21,2225.53 2120,2214.75 R233.1@2311.38,2214.75
NetR234_1: R234.1 UADS1.19 | length 179
  Layer 1 - Top Layer w10: UADS1.19@2134.8,2265.53 2274.21,2265.53 2280,2259.75 R234.1@2311.38,2259.75
NetR235_1: R235.1 UADS1.20 | length 184.7
  Layer 1 - Top Layer w10: UADS1.20@2134.8,2285.22 2225.47,2285.22 2245,2304.75 R235.1@2311.38,2304.75
NetR240_1: R240.1 UADS2.18 | length 208.8
  Layer 1 - Top Layer w10: UADS2.18@1884.21,1089.94 1884.21,1075.53 1895,1064.75 1965,1064.75 2020,1009.75 R240.1@2051.38,1009.75
NetR250_2: R250.2 REN0.2 U1.5 | length 165.9
  Layer 1 - Top Layer w20: REN0.2@1355,781.12 U1.5@1355,840.61 v1(1355,879.75)
  Layer 4 - Bottom Layer w20: v1(1355,879.75) 1388,879.75 1395,886.75 R250.2@1395,911.12
NetR252_2: R252.2 REN1.2 U2.5 | length 135.4
  Layer 1 - Top Layer w20: REN1.2@1351.38,1119.75 1355,1123.37 U2.5@1355,1170.61 v1(1355,1209.75)
  Layer 4 - Bottom Layer w20: v1(1355,1209.75) 1383.84,1209.75 R252.2@1394.48,1220.39
NetR256_1: R256.1 U33.14 | length 75.9
  Layer 1 - Top Layer w10: U33.14@3166.14,2148.13 3239.76,2148.13 R256.1@3241.38,2149.75
NetR257_1: R257.1 U33.12 | length 76.2
  Layer 1 - Top Layer w10: U33.12@3166.14,2096.95 3239.18,2096.95 R257.1@3241.38,2094.75
NetR258_2: R258.2 R259.2 R260.2 | length 91.2
  Layer 1 - Top Layer w30: R260.2@2153.62,2704.75 R259.2@2153.62,2664.75 2153.62,2617.62 R258.2@2156.5,2614.75
NetR261_2: R261.2 R262.1 R263.1 | length 87.1
  Layer 1 - Top Layer w30: R261.2@1913.62,1482.62 R263.1@1913.62,1569.75
NetR278_1: R278.1 U33.10 | length 75.7
  Layer 1 - Top Layer w10: U33.10@3166.14,2045.77 3240.36,2045.77 R278.1@3241.38,2044.75
NetR279_2: R279.2 U13.2 U13.3 U13.4 | length 115
  Layer 4 - Bottom Layer w10: U13.2@4145.2,2519.19 U13.3@4145.2,2493.6 U13.4@4145.2,2468.01 4145.2,2411.83 R279.2@4150.63,2406.39
NetR280_2: R280.2 U14.2 U14.3 U14.4 | length 115
  Layer 4 - Bottom Layer w10: U14.2@4148.21,844.49 U14.3@4148.21,818.9 U14.4@4148.21,793.31 4148.21,737.13 R280.2@4153.65,731.69
NetR284_2: R284.2 UADS1.4 UADS1.8 | length 337.8
  Layer 1 - Top Layer w10: R284.2@1938.62,2429.75 v1(1938.62,2395.43) 1938.62,2361.12 1955.47,2344.27 UADS1.8@1985.2,2344.27 ; v1(2035,2454.75) 2050.16,2439.59 UADS1.4@2050.16,2389.55
  Layer 4 - Bottom Layer w10: v1(1938.62,2395.43) 1938.62,2435.02 1958.35,2454.75 v1(2035,2454.75)
NetR288_2: R288.2 UADS2.4 UADS2.8 | length 331.8
  Layer 1 - Top Layer w10: R288.2@1713.62,1274.75 v1(1713.62,1245.43) 1713.62,1211.12 1730.47,1194.27 UADS2.8@1760.2,1194.27 ; v1(1810,1304.75) 1825.16,1289.59 UADS2.4@1825.16,1239.55
  Layer 4 - Bottom Layer w10: v1(1713.62,1245.43) 1713.62,1283.37 1735,1304.75 v1(1810,1304.75)
NetR404_2: R404.2 U401.7 | length 138.2
  Layer 4 - Bottom Layer w10: U401.7@2521.14,3486.02 2553.98,3486.02 2560,3480 2560,3423.5 R404.2@2531.5,3395
NetR453_2: R453.2 R454.2 U415.5 | length 122.2
  Layer 1 - Top Layer w15: U415.5@624.13,1579.75 675,1579.75 R453.2@675,1606.12 R454.2@720,1606.12
NetRDN3_2: RDN3.2 RDN4.2 | length 64.1
  Layer 1 - Top Layer w8: RDN3.2@1146.18,1264.75 1169.75,1264.75 1186,1281 RDN4.2@1203.5,1281
NetRDP3_2: RDP3.2 RDP4.2 | length 57
  Layer 1 - Top Layer w8: RDP3.2@1146.5,959.75 RDP4.2@1203.5,959.75
NetRenb2_2: Renb2.2 Rent2.1 U23.3 | length 365
  Layer 1 - Top Layer w30: Renb2.2@3111.5,3705 Rent2.1@3168.5,3705 ; Rent2.1@3169.15,3705 3169.15,3630.85 3180,3620 3310,3620 3320,3610 U23.3@3394.37,3610
NetRenb3_2: Renb3.2 Rent3.1 U5.3 | length 421.7
  Layer 1 - Top Layer w30: Renb3.2@2277.5,624 2342.5,624 Rent3.1@2343.5,625 2343.5,529.5 2394,479 U5.3@2582.37,479
NetRenb_2: Renb.2 Rent.1 U22.3 | length 422.4
  Layer 1 - Top Layer w25: U22.3@719.63,3058 719.63,3056.32 830,3056.32 895,2991.32 892.5,2988.82 892.5,2852.5 Renb.2@890,2850 Rent.1@815,2850
NetRES3V_2: RES3V.2 U3P8V.19 | length 115.4
  Layer 4 - Bottom Layer w10: RES3V.2@980,256.5 1000,276.5 1000,317.95 1017.36,335.32 U3P8V.19@1038.46,335.32
NetRES5V_2: RES5V.2 U5P5V.19 | length 115.9
  Layer 4 - Bottom Layer w10: U5P5V.19@3626.54,3599.69 3648.47,3599.69 3665,3616.21 3665,3650 3685,3670 RES5V.2@3685,3678.5
NetRES18V_2: RES18V.2 U18P5V.19 | length 112.7
  Layer 4 - Bottom Layer w10: RES18V.2@820,2991.5 840,3011.5 840,3048.32 862,3070.31 U18P5V.19@878.46,3070.31
NetRon2_1: Ron2.1 U23.2 | length 77.9
  Layer 1 - Top Layer w30: Ron2.1@3316.5,3660 U23.2@3394.37,3660
NetRon3_1: Ron3.1 U5.2 | length 105.6
  Layer 1 - Top Layer w30: Ron3.1@2484,546.5 2501.5,529 U5.2@2582.37,529
NetRon_1: Ron.1 U22.2 | length 76.9
  Layer 1 - Top Layer w25: U22.2@719.63,3008 Ron.1@796.5,3008
NetTPPGOOD_1: TPPGOOD.1 U401.8 | length 302.6
  Layer 3 - PWR w15: v2(2521.14,3440) 2536.14,3455 v2(2740,3455)
  Layer 4 - Bottom Layer w10: v2(2740,3455) 2740,3440 2745,3435 TPPGOOD.1@2780,3435
  Layer 4 - Bottom Layer w15: v2(2521.14,3440) U401.8@2521.14,3460.43
NISO_SCL_DIF: J4.58 U13.6 | length 483.4
  Layer 1 - Top Layer w10: v1(3797.01,2276.39) 3797.01,2251.39 3847.91,2200.49 J4.58@3920.02,2200.49
  Layer 4 - Bottom Layer w10: v1(3797.01,2276.39) 3797.01,2451.39 3839.21,2493.6 U13.6@3918.82,2493.6
NISO_SCL_SERI: J7.58 U14.6 | length 442.7
  Layer 1 - Top Layer w10: v1(3810.02,626.69) 3810.02,591.69 3840.93,560.79 J7.58@3928.52,560.79
  Layer 4 - Bottom Layer w10: v1(3810.02,626.69) 3810.02,771.69 3857.23,818.9 U14.6@3921.84,818.9
NISO_SDA_DIF: J4.56 U13.5 | length 386.3
  Layer 1 - Top Layer w10: v1(3832.01,2276.39) 3832.01,2256.39 3868.21,2220.19 J4.56@3920.51,2220.19
  Layer 4 - Bottom Layer w10: v1(3832.01,2276.39) 3832.01,2441.39 3858.62,2468.01 U13.5@3918.82,2468.01
NISO_SDA_SERI: J7.56 U14.5 | length 345.1
  Layer 1 - Top Layer w10: v1(3845.02,626.69) 3845.02,606.69 3871.23,580.49 J7.56@3928.52,580.49
  Layer 4 - Bottom Layer w10: v1(3845.02,626.69) 3845.02,771.69 3866.64,793.31 U14.5@3921.84,793.31
OPAN1_N: C72.2 OPAP_1.3 R98.2 | length 122
  Layer 1 - Top Layer w8: R98.2@676,2465.5 C72.2@736,2465.5 736.76,2464.75 OPAP_1.3@797.72,2464.75
OPAN1_P: C71.2 OPAN_1.3 R97.2 | length 121
  Layer 1 - Top Layer w8: R97.2@677,2165.5 C71.2@736,2165.5 736.76,2164.74 OPAN_1.3@797.71,2164.74
OPAN2_N: C97.2 OPAP_2.3 R108.2 | length 123.9
  Layer 1 - Top Layer w8: R108.2@675.7,1268.5 676.05,1268.84 C97.2@735.7,1268.84 739.8,1264.75 OPAP_2.3@797.72,1264.75
OPAN2_P: C96.2 OPAN_2.3 R107.2 | length 130.6
  Layer 1 - Top Layer w5: R107.2@668.7,968.5 R107.2@673.7,968.5
  Layer 1 - Top Layer w8: R107.2@673.7,968.5 R107.2@676,968.5 C96.2@736,968.5 739.76,964.75 OPAN_2.3@797.72,964.75
PRE: C40.1 D2.1 L1.1 U9.14 U9.15
REFBUF_DIF: C322.1 UADS1.5 UADS1.7 | length 165
  Layer 1 - Top Layer w10: UADS1.7@1985.2,2364.75 C322.1@1985.2,2448.45 ; C322.1@1990,2453.25 1991.5,2453.25 2030.47,2414.27 UADS1.5@2030.47,2389.55
REFBUF_SE: C323.1 UADS2.5 UADS2.7 | length 171
  Layer 1 - Top Layer w10: UADS2.7@1760.2,1214.75 1760.2,1298.45 C323.1@1765,1303.25 1805.47,1262.78 UADS2.5@1805.47,1239.55
REFOUT: R485.1 RR413.2 RR457.2 TPV4.1 U422.6 | length 951.5
  Layer 1 - Top Layer w17: U422.6@1645.6,1624.2 1701.55,1624.2 ; 1704.29,1626.95 1705,1626.24
  Layer 1 - Top Layer w40: R485.1@1005,1494.75 1040,1459.75 1690,1459.75 1715,1484.75 1715,1521.24 RR413.2@1711.5,1524.75 ; TPV4.1@1805,1679.75 TPV4.1@1810,1684.75 1827,1701.75 RR457.2@1914.12,1701.75
RVS_DIF: R71.1 UADS1.21 | length 1923.4
  Layer 1 - Top Layer w10: UADS1.21@2134.8,2304.9 2218.38,2304.9 2243.22,2329.75 2475.15,2329.75 2625,2479.6 2625,2616.11 2720.29,2711.39 3433.61,2711.39 3484,2661 v2(3484,2660) ; v2(3658.61,2486.39) R71.1@3714.12,2486.39 R71.1@3712.73,2487.78
  Layer 4 - Bottom Layer w10: v2(3484,2660) 3657.61,2486.39 v2(3658.61,2486.39)
RVS_SE: R82.1 UADS2.21 | length 1960.3
  Layer 1 - Top Layer w10: UADS2.21@1909.8,1154.9 1976.37,1154.9 2018.23,1196.77 2140.02,1196.77 2421.79,915 2423,915 2424,914 3559.85,914 3628.85,845 3704.71,845 R82.1@3706.4,846.69
SCL: J3.3 R89.1 U15.8 | length 556.1
  Layer 1 - Top Layer w10: J3.3@3035,1399.75 3035,1439.75 3005,1469.75 R89.1@3005,1491.12 3151.38,1491.12 3175,1514.75 3175,1704.75 3150,1729.75 U15.8@3102.8,1729.75
SCLK_PHI: R69.1 R80.1 UADS1.23 UADS2.23 | length 5559.9
  Layer 1 - Top Layer w10: UADS2.23@1909.8,1194.27 1964.53,1194.27 2015.25,1245 2216.21,1245 2510.21,951 v2(3485,951) 3619,951 3635,935 3704.71,935 R80.1@3706.4,936.69 ; UADS1.23@2134.8,2344.27 2199.53,2344.27 2235,2379.75 2482.72,2379.75 2570,2467.02 2570,2582.32 2714.07,2726.39 3447.82,2726.39 3515,2659.21 v2(3515,2659) ; v2(3485,2352) 3498,2365 3498,2495 3580,2577 v2(3657,2577) 3657.61,2576.39 R69.1@3714.12,2576.39 R69.1@3711.72,2578.79
  Layer 4 - Bottom Layer w10: v2(3485,951) v2(3485,2352) ; v2(3515,2659) 3518,2659 3600,2577 v2(3657,2577)
SDA: J3.2 R88.1 U15.7 | length 628.6
  Layer 1 - Top Layer w10: U15.7@2877.2,1729.75 2790,1729.75 2750,1689.75 2750,1534.75 2793.62,1491.12 R88.1@2960,1491.12 2960,1464.75 2935,1439.75 J3.2@2935,1399.75
SDI: R66.1 R77.1 UADS1.22 UADS2.22 | length 5567.1
  Layer 1 - Top Layer w10: UADS2.22@1909.8,1174.59 1974.84,1174.59 2012.25,1212 2146,1212 2428,930 3605,930 v2(3610,925) ; UADS1.22@2134.8,2324.59 2209.84,2324.59 2240,2354.75 2478.93,2354.75 2585,2460.81 2585,2529.75 v2(2600,2544.75) ; v2(3627,2712) 3627.61,2711.39 R66.1@3714.12,2711.39 R66.1@3713.51,2712 ; v2(3660,1071) 3705.71,1071 R77.1@3706.4,1071.69 R77.1@3706.35,1071.75
  Layer 4 - Bottom Layer w10: v2(2600,2544.75) 2600,2547.89 2744.11,2692 3607,2692 v2(3627,2712) 3699.29,2712 3706.4,2704.89 3706.4,1116.69 3705.69,1116.69 v2(3660,1071) 3610,1021 v2(3610,925)
SDO0_DIF: R72.1 R235.2 | length 1658
  Layer 1 - Top Layer w10: R235.2@2358.62,2304.75 2471.36,2304.75 2640,2473.39 2640,2551.84 v2(2683.95,2595.79) ; v2(3658,2439) 3660.39,2441.39 R72.1@3714.12,2441.39 R72.1@3712.12,2439.4
  Layer 4 - Bottom Layer w10: v2(2683.95,2595.79) 2765.16,2677 3420,2677 v2(3658,2439)
SDO0_SE: R83.1 R226.2 | length 1751.5
  Layer 1 - Top Layer w10: R226.2@2098.62,1145 2165,1145 2411,899 3553.64,899 3652.64,800 3704.71,800 R83.1@3706.4,801.69 R83.1@3706.35,801.75
SDO1_DIF: R73.1 R234.2 | length 1650.9
  Layer 1 - Top Layer w10: R234.2@2358.62,2259.75 2455,2259.75 2655,2459.75 2655,2530.79 v2(2701.98,2577.77) ; v2(3659,2395) 3712.73,2395 R73.1@3714.12,2396.39
  Layer 4 - Bottom Layer w10: v2(2701.98,2577.77) 2757.21,2633 3418,2633 3656,2395 v2(3659,2395)
SDO1_SE: R84.1 R225.2 | length 1732.7
  Layer 1 - Top Layer w10: R225.2@2098.62,1054.75 2155,1054.75 2325.75,884 3547.43,884 3676.43,755 3704.71,755 R84.1@3706.4,756.69 R84.1@3706.35,756.75
SDO2_DIF: R74.1 R233.2 | length 1672.9
  Layer 1 - Top Layer w10: R233.2@2358.62,2214.75 2435,2214.75 2670,2449.75 2670,2509.75 v2(2720,2559.75) ; v2(3660,2349) 3662.39,2351.39 R74.1@3714.12,2351.39 R74.1@3712.12,2349.4
  Layer 4 - Bottom Layer w10: v2(2720,2559.75) 2778.25,2618 3391,2618 v2(3660,2349)
SDO2_SE: R85.1 R240.2 | length 1732.6
  Layer 1 - Top Layer w10: R240.2@2098.62,1009.75 2145,1009.75 2285.75,869 3541.21,869 3700.21,710 3704.71,710 R85.1@3706.4,711.69
SDO3_DIF: R75.1 R232.2 | length 1687.1
  Layer 1 - Top Layer w10: R232.2@2358.62,2169.75 2420,2169.75 2685,2434.75 2685,2484.75 v2(2740,2539.75) ; v2(3661,2307) 3661.61,2306.39 R75.1@3714.12,2306.39
  Layer 4 - Bottom Layer w10: v2(2740,2539.75) 2803.25,2603 3365,2603 v2(3661,2307)
SDO3_SE: R86.1 R223.2 | length 1723.1
  Layer 1 - Top Layer w10: R223.2@2105,868.37 R223.2@2098.62,874.75 2258.79,874.75 2279.53,854 3535,854 3680.66,708.34 3680.66,695.74 3686.51,689.88 3699.12,689.88 3704.71,684.29 3704.71,665 R86.1@3706.4,666.69
SRESETN: R65.1 R76.1 UADS1.2 UADS2.2 | length 5187.7
  Layer 1 - Top Layer w10: UADS2.2@1864.53,1239.55 1865,1240.02 1865,1261.36 1926.25,1261.36 1961.89,1297 2297,1297 2333.5,1333.5 ; UADS1.2@2089.53,2389.55 2090,2390.02 2090,2414.75 2188.79,2414.75 2213.79,2439.75 2291.36,2439.75 2396.36,2544.75 v2(2490,2544.75) 2701.65,2756.39 R65.1@3714.12,2756.39 ; v2(2520,2234.75) 2520,1965 2475,1920 2390,1920 2370,1900 2370,1370 2333.5,1333.5 ; R76.1@3706.4,1116.69 3137.41,1116.69 2904.36,1349.75 2806.07,1349.75 2758.63,1302.3 2678.76,1302.3 2672.03,1309.04 2651.93,1309.04 2636.22,1324.75 2521.72,1324.75 2513.27,1316.3 2350.7,1316.3 2333.5,1333.5
  Layer 4 - Bottom Layer w10: v2(2490,2544.75) 2470,2524.75 2470,2284.75 v2(2520,2234.75)
SS: C34.1 U9.10 | length 82.1
  Layer 1 - Top Layer w10: U9.10@2237.2,3631.02 2270.47,3631.02 C34.1@2305,3596.5
SYSCLK0: R95.2 TP16.1 U18.2 U31.2 | length 2139.3
  Layer 1 - Top Layer w10: v1(2695,1379.75) 2715.21,1359.53 U31.2@2715.21,1329.04 ; v1(3077.6,2473.54) 3097.81,2453.33 U18.2@3097.81,2422.84 ; R95.2@3288.63,2199.75 v1(3288.63,2243.37) 3305,2259.75 3375,2259.75 TP16.1@3385,2269.75
  Layer 4 - Bottom Layer w10: v1(2695,1379.75) 2695,1809.75 2765,1879.75 3235,1879.75 3288.63,1933.37 v1(3288.63,2243.37) 3288.63,2486.12 3270,2504.75 3090,2504.75 3077.6,2492.34 v1(3077.6,2473.54)
SYSCLK1: R70.1 R81.1 R256.2 TP31.1 | length 2159
  Layer 1 - Top Layer w10: R256.2@3288.63,2149.75 3325,2149.75 3345,2169.75 TP31.1@3385,2169.75 ; v2(3550,1151) 3550,2004.75 TP31.1@3385,2169.75 ; v2(3657,891) 3657.69,891.69 R81.1@3706.4,891.69 ; R70.1@3714.12,2531.39 3713.73,2531 3565,2531 3546,2512 3546,2330.75 TP31.1@3385,2169.75
  Layer 4 - Bottom Layer w10: v2(3550,1151) 3550,950 3608,892 3656,892 v2(3657,891)
SYSCLK2: R257.2 TP32.1 | length 106.7
  Layer 1 - Top Layer w10: R257.2@3288.63,2094.75 3315,2094.75 3340,2069.75 TP32.1@3385,2069.75
SYSCLK3: R278.2 TP33.1 | length 153
  Layer 1 - Top Layer w10: R278.2@3288.63,2044.75 3288.63,2001.12 3320,1969.75 TP33.1@3385,1969.75
V_CM: C84.1 FDA1.9 R214.2 R215.2 R216.2 TP29.1 | length 1301
  Layer 1 - Top Layer w10: FDA1.9@1495.12,2283.75 1495.12,2269.63 1505,2259.75 v1(1520,2259.75) 1576.5,2259.75 C84.1@1586.5,2249.75
  Layer 1 - Top Layer w20: R216.2@1061.5,1682.38 1118.5,1682.38 R215.2@1125,1675.88 1131.5,1682.38 R214.2@1188.5,1682.38 1188.5,1590.88 TP29.1@1180,1582.38 v1(1272.37,1582.38)
  Layer 4 - Bottom Layer w20: v1(1272.37,1582.38) 1320,1630.01 1320,2194.75 1385,2259.75 v1(1520,2259.75)
V_CM_OPA: C108.1 C318.1 R213.1 R214.1 | length 952.3
  Layer 1 - Top Layer w15: v1(1251.5,1649.75) R214.1@1251.5,1682.38 C318.1@1251.5,1737.38
  Layer 4 - Bottom Layer w15: C108.1@1081.5,959.75 R213.1@1146.38,959.75 1146.38,981.12 1160,994.75 1160,1114.75 1080,1194.75 1080,1478.25 v1(1251.5,1649.75)
V_REF_OPA0: C109.1 C115.1 R110.2 R213.2 TP30.1 U1.3 U2.3 | length 725.8
  Layer 1 - Top Layer w20: v1(1305,899.75) 1317.6,912.34 U1.3@1317.6,948.88 ; v1(1305,1224.75) 1317.6,1237.34 U2.3@1317.6,1278.88
  Layer 4 - Bottom Layer w10: TP30.1@1115,819.75 TP30.1@1116.5,819.75 ; R110.2@1193.62,912.62 R110.2@1201.5,904.75 ; C109.1@1256.5,904.75 C109.1@1260,901.24
  Layer 4 - Bottom Layer w20: TP30.1@1116.5,819.75 R110.2@1201.5,904.75 C109.1@1256.5,904.75 ; R110.2@1193.62,912.62 R213.2@1193.62,959.75 1193.62,1093.37 1266.5,1166.24 C115.1@1266.5,1204.75 1305,1204.75 v1(1305,1224.75) ; C109.1@1266.5,899.75 v1(1305,899.75)
VDD: C339.1 C340.1 L10.1 U33.2 U33.3 U33.4 U33.7
VDDO: C348.1 C349.1 C350.1 L12.1 U33.11 U33.15
  other v1: 3105,2074.75 3105,2119.75 3105,2164.75
VEE: J39.2 R248.2 R250.1 R252.1 U1.2 U2.2 | length 3850.7
  Layer 1 - Top Layer w20: v1(1355,911.12) U1.2@1355,948.88 ; v1(1355,1239.43) U2.2@1355,1278.88 ; R248.2@1503.62,2454.75 1553.5,2454.75 1560,2461.24
  Layer 1 - Top Layer w30: 1560,2461.24 v1(1595,2461.24)
  Layer 4 - Bottom Layer w20: v1(1355,911.12) 1355,946.99 1366.38,958.37 ; v1(1355,1239.43) 1355,1259.75 1362.89,1267.63 R252.1@1394.48,1267.63
  Layer 4 - Bottom Layer w40: v1(1595,2461.24) 1623.5,2461.24 1655,2429.75 1655,2094.75 1620,2059.75 1490,2059.75 1394.48,1964.23 R252.1@1394.48,1267.63 1467.11,1267.63 1490,1244.75 1490,1079.75 1465,1054.75 1365,1054.75 1345,1034.75 1345,979.75 1366.38,958.37 1503.62,958.37 1610,1064.75 1675,1064.75 1700,1039.75 1700,929.75 1857.25,772.5 2177.5,772.5 2380,570 2659.98,570 J39.2@2662.98,573 J39.2@2678.02,573
VIN+_1_N: J15.1 R98.1 | length 235.6
  Layer 1 - Top Layer w8: J15.1@465,2588 575,2588 634,2529 675.5,2529 R98.1@676,2528.5
VIN+_1_P: J14.1 R97.1 | length 235.6
  Layer 1 - Top Layer w8: J14.1@465,2169 575,2169 634,2228 675.5,2228 R97.1@676,2228.5
VIN+_2_N: J19.1 R108.1 | length 281.5
  Layer 1 - Top Layer w8: J19.1@465,1328 559.47,1328 632,1255.47 632,1222 649,1205 675.2,1205 R108.1@675.7,1205.5
VIN+_2_P: J18.1 R107.1 | length 280.7
  Layer 1 - Top Layer w8: J18.1@465,909 559.47,909 632,981.53 ; 632,983.53 632,1016.54 647.46,1032 675.5,1032 R107.1@676,1031.5
VREF: R56.2 R218.2 R255.2 R259.1 R262.2 R457.2 RR457.1 | length 3524.6
  Layer 1 - Top Layer w20: R218.2@1235,1820.88 R218.2@1235.66,1820.22
  Layer 1 - Top Layer w40: R457.2@530,1979.75 877.14,1979.75 942.14,2044.75 ; 941.49,2044.75 942.14,2044.75 ; R218.2@1235.66,1820.22 1310,1820.22 1310,2044.75 ; v1(1735,2139.75) v1(1735,2104.75) v1(1735,2074.75) ; v1@1735,2489.75 v1(1735,2494.75) v1(1735,2529.75) v1(1735,2564.75) 1835,2664.75 R259.1@2106.38,2664.75 ; 1849.82,1944.57 1810,1984.39 1810,1984.75 1735,2059.75 v1(1735,2074.75) ; 1850,1944.75 1945,1944.75 1968.62,1921.12 R56.2@1968.62,1769.75 1968.62,1648.37 1940,1619.75 1800,1619.75 1785,1604.75 1785,1529.75 R262.2@1866.38,1529.75 ; 942.14,2044.75 1310,2044.75 ; 1310,2044.75 1705,2044.75 v1(1735,2074.75)
  Layer 4 - Bottom Layer w40: v1(1735,2074.75) v1(1735,2104.75) v1(1735,2139.75) v1(1735,2494.75) v1(1735,2529.75) v1(1735,2564.75)
VREF1: R255.1 R260.1 R263.2 | length 6729
  Layer 1 - Top Layer w20: v1(1830,1574.75) R263.2@1866.38,1574.75 ; R255.1@2018.62,1654.75 v1(2085,1654.75) ; v1(2070,2709.75) R260.1@2106.38,2709.75
  Layer 4 - Bottom Layer w10: v1(1830,1574.75) 1878.19,1574.75 1921.05,1531.88 1921.05,1462.26 1877.05,1418.25 1811.5,1418.25 1720,1509.75 1695,1509.75 1650,1464.75 1500,1464.75 1480,1484.75 1480,1529.75 1505,1554.75 1735,1554.75 1750,1569.75 1750,1609.75 1720,1639.75 1465,1639.75 1435,1609.75 1435,1469.3 1479.55,1424.75 1545,1424.75 1570,1399.75 1660,1399.75 1715,1344.75 1820,1344.75 1850.57,1314.17 1850.57,1284.17 1872.55,1262.2 1897.45,1262.2 1919.45,1284.19 1919.45,1424.43 1955,1459.98 1955,1554.75 1975,1574.75 2050,1574.75 2085,1609.75 v1(2085,1654.75) 2085,1669.75 2120,1704.75 2120,1949.39 1991.85,2077.54 1991.85,2328.29 2095,2431.44 2095,2619.75 2094.84,2619.75 2157.67,2682.57 2157.67,2739 781,2739 767,2725 767,2712 792,2687 1490.97,2687 1516.72,2712.75 2067,2712.75 v1(2070,2709.75)
WP1_0: C54.2 C262.1 J5.1 R64.1 U13.7 | length 1196.8
  Layer 4 - Bottom Layer w10: J5.1@3500,2855 3500.6,2854.4 3835.6,2854.4 3852.01,2837.99 3852.01,2539.19 3872.01,2519.19 U13.7@3918.82,2519.19 3979.22,2519.19 4012.01,2486.39 C262.1@4012.01,2396.39 4062.01,2396.39 4077.01,2381.39 4077.01,2361.39 4169.8,2361.39 R64.1@4227.66,2419.25 ; R64.1@4227.01,2418.61 R64.1@4227.01,2419.9
WP1_1: C56.2 C261.1 J6.1 R87.1 U14.7 | length 1105.1
  Layer 4 - Bottom Layer w10: J6.1@3459,604 3463,600 3750,600 3760,610 3760,766.67 3837.82,844.49 U14.7@3921.84,844.49 3982.23,844.49 4015.02,811.69 C261.1@4015.02,721.69 4065.03,721.69 4080.03,706.69 4080.03,686.7 4115.03,686.7 4130.02,701.69 4187.81,701.69 R87.1@4220.03,733.91
pads on no net: FID1.1 FID2.1 FID3.1 FID4.1 FID5.1 FID6.1 H1.1 H2.1 H3.1 H4.1 H9. H11. H13. H15. J4.2 J4.3 J4.4 J4.5 J4.6 J4.7 J4.8 J4.9 J4.10 J4.11 J4.12 J4.13 J4.14 J4.15 J4.17 J4.19 J4.21 J4.23 J4.25 J4.26 J4.27 J4.29 J4.31 J4.33 J4.35 J4.36 J4.37 J4.39 J4.41 J4.43 J4.45 J4.46 J4.47 J4.48 J4.49 J4.51 J4.52 J4.53 J4.54 J4.55 J4.57 J4.MH1 J4.MH2 J7.2 J7.3 J7.4 J7.5 J7.6 J7.7 J7.8 J7.9 J7.10 J7.11 J7.12 J7.13 J7.14 J7.15 J7.17 J7.19 J7.21 J7.23 J7.25 J7.26 J7.27 J7.29 J7.31 J7.33 J7.35 J7.36 J7.37 J7.39 J7.41 J7.43 J7.45 J7.46 J7.47 J7.48 J7.49 J7.51 J7.52 J7.53 J7.54 J7.55 J7.57 J7.MH1 J7.MH2 OPAN_1.1 OPAN_1.5 OPAN_1.8 OPAN_2.1 OPAN_2.5 OPAN_2.8 OPAP_1.1 OPAP_1.5 OPAP_1.8 OPAP_2.1 OPAP_2.5 OPAP_2.8 U3P8V.3 U3P8V.4A U3P8V.4B U3P8V.8A U3P8V.8B U3P8V.9A U3P8V.9B U3P8V.9C U3P8V.9D U3P8V.10A U3P8V.10B U3P8V.14A U3P8V.14B U5P5V.3 U5P5V.4A U5P5V.4B U5P5V.8A U5P5V.8B U5P5V.9A U5P5V.9B U5P5V.9C U5P5V.9D U5P5V.10A U5P5V.10B U5P5V.14A U5P5V.14B U9.2 U9.4 U11.3 U11.7 U15.1@2874.25,1656.91 U15.1@2905.75,1656.91 U15.2@2974.25,1656.91 U15.2@3005.75,1656.91 U15.3@3074.25,1656.91 U15.3@3105.75,1656.91 U15.4@3074.25,1802.58 U15.4@3105.75,1802.58 U15.5@2974.25,1802.58 U15.5@3005.75,1802.58 U15.6@2874.25,1802.58 U15.6@2905.75,1802.58 U18P5V.3 U18P5V.4A U18P5V.4B U18P5V.8A U18P5V.8B U18P5V.9A U18P5V.9B U18P5V.9C U18P5V.9D U18P5V.10A U18P5V.10B U18P5V.14A U18P5V.14B U19.1 U32.1 U33.8 U401.17@2405,3550 U422.1 U422.3 U422.5 U422.7 U422.8 UADS1.6 UADS2.6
